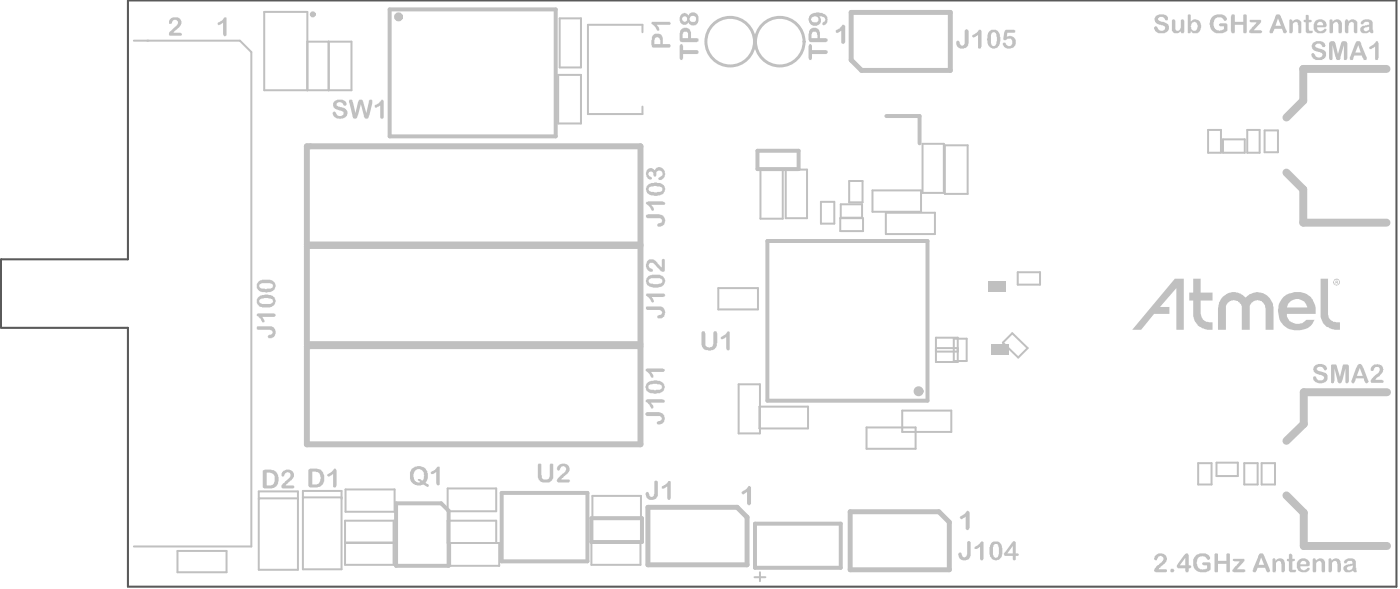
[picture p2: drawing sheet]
<svg xmlns="http://www.w3.org/2000/svg" width="238mm" height="100mm" viewBox="0 0 238 100" stroke-linecap="round" stroke-linejoin="round" font-family="sans-serif">
<circle cx="25.1" cy="6.9" r=".17" fill="#c0c0c0"/>
<g fill="none" stroke="#c0c0c0" stroke-width=".34">
<path d="M22.8 6.9h18.1l1.9 2v84.1h-20M52.4 7.1h7.5v8.3h-14.9v-13.4h7.4v13.4M56 7.1v8.3M95.1 12.7h3.9v8.3h-3.9zM95.3 3.1h3.7v8.4h-3.7zM109.4 5.5v-1.3h-9.3v15.2h9.3v-1.3M129.5 28.8h3.8v8.4h-3.8zM133.8 28.8h3.7v8.3h-3.7zM139.8 34.3h2.3v3.7h-2.3zM143.1 37.1h3.9v2.2h-3.9zM143.2 34.8h3.6v2.2h-3.6zM144.7 30.8h2.2v3.6h-2.2z"/>
<path d="M148.6 32.4h8.3v3.6h-8.3zM150.9 36.2h8.4v3.6h-8.4zM157.1 24.5h3.7v8.3h-3.7zM160.9 24.7h3.9v8.3h-3.9zM205.8 22.1h2.2v3.9h-2.2zM208.3 23.7h3.7v2.3h-3.7zM212.5 22.1h2.1v3.9h-2.1zM215.4 22.2h2.3v3.7h-2.3zM122.4 49h6.7v3.6h-6.7zM159.4 57.4h3.7v4.2h-3.7zM159.4 59.2h3.7M159.4 59.8h3.7"/>
<path d="M162.5 57.6h2.2v3.8h-2.2zM170.8 58.3l1.6-1.6 2.6 2.5-1.6 1.6zM173.4 46.3h3.8v2.1h-3.8zM125.8 65.4h3.7v8.3h-3.7zM129.4 69.2h8.2v3.7h-8.2zM147.6 72.7h8.4v3.6h-8.4zM153.7 69.8h8.3v3.7h-8.3zM204.1 78.8h2.3v3.6h-2.3zM207.2 78.7h3.7v2.3h-3.7zM212 78.8h2.2v3.6h-2.2zM214.9 78.8h2.3v3.6h-2.3zM30.2 93.7h8.4v3.6h-8.4z"/>
<path d="M44.1 83.6h6.6v13.3h-6.6zM50.7 84.8l-6.6 .1M51.6 83.5h6.6v13.3h-6.6zM58.2 84.6l-6.6 .1M58.8 88.6h8.2v7.5h-8.2zM58.8 92.3h8.2M58.8 92.4h8.2M58.9 83.3h8.3v3.8h-8.3zM76.3 83.1h8.2v3.9h-8.2zM76.7 92.4v3.8h8.3v-3.8h-8.7v-3.8h8.2v3.8M100.7 92.4h8.4v3.7h-8.4zM100.9 84.4h8.3v3.7h-8.3z"/>
<path d="M128.5 98.2h1.9M129.5 97.3v1.6"/>
</g>
<path d="M52.3 24.9h56.8v16.7h-56.8zM52.3 58.9h56.8v16.7h-56.8zM52.3 41.8h56.8v16.7h-56.8z" fill="none" stroke="#c0c0c0" stroke-width="1"/>
<path d="M66.4 1.6h28.3v21.6h-28.3zM151 19.7h5.6v4.7M129 25.6h7v3.2h-7zM130.7 41h27.3v27.2h-27.3zM67.5 85.6h7.7l1.2 1.3v9.3h-8.9zM85.5 83.8h14.6v11.7h-14.6zM100.7 88.1h8.7v4.1h-8.7zM128.6 89.1h14.6v7.5h-14.6z" fill="none" stroke="#c0c0c0" stroke-width=".68"/>
<path d="M145 2.1h16.9v9.9h-15.1l-1.8-1.8zM110.4 86.3h15.2l1.7 1.7v8.1h-16.9zM144.8 87.1h15.1l1.8 1.7v8.1h-16.9z" fill="none" stroke="#c0c0c0" stroke-width=".84"/>
<path d="M236.2 11.7h-14.2v5.4l-2.9 2.9M219.1 29.4l2.9 2.8v5.7h14.2M236.3 66.7h-14.2v5.4l-3 2.9M219.1 84.3l3 2.9v5.7h14.2" fill="none" stroke="#c0c0c0" stroke-width="1.4"/>
<g fill="#c0c0c0">
<path d="M168.4 47.8h2.9v1.9h-2.9z" fill-rule="evenodd"/>
<path d="M168.8 58.6h3v1.8h-3z" fill-rule="evenodd"/>
</g>
<g fill="#c0c0c0">
<path d="M119.5 56.5l.1-.1a.28 .28 0 0 1 .3-.1 .28 .28 0 0 1 .2 .4l.1 1.6a.64 .64 0 0 0 .2 .7 .64 .64 0 0 0 .7 0h.1a.71 .71 0 0 0 .3-.7v-1.6a.34 .34 0 0 1 .4-.4 .34 .34 0 0 1 .3 .4v1.7a1.32 1.32 0 0 1-1.9 1.2 1.24 1.24 0 0 1-.8-1.3z"/>
<path d="M122.8 57.4l.2-.2a1.4 1.4 0 0 0 1-.9l.3 .1v2.9a.3 .3 0 0 1-.3 .3 .3 .3 0 0 1-.3-.3v-2l-.2 .1a.55 .55 0 0 1-.7 .2z"/>
<path d="M126.3 83.7l.3-.2a1.14 1.14 0 0 0 .8-.8 .34 .34 0 0 1 .4 .1 .34 .34 0 0 1 .1 .3v2.3a.36 .36 0 0 1-.2 .6 .36 .36 0 0 1-.4-.5v-1.8l-.2 .1a.43 .43 0 0 1-.7 .2z"/>
<path d="M91.7 78.9h.1a.28 .28 0 0 1 .3 0 .28 .28 0 0 1 .1 .3l.1 1.7a.59 .59 0 0 0 .2 .6 .59 .59 0 0 0 .6 .1h.1a.63 .63 0 0 0 .4-.8v-1.6a.3 .3 0 0 1 .3-.3 .3 .3 0 0 1 .3 .3v1.5a1.19 1.19 0 0 1-1.6 1.4 1.07 1.07 0 0 1-1-1.4z"/>
<path d="M95 79.3a1.15 1.15 0 0 1 1.1-.4 1.15 1.15 0 0 1 .9 .8 1.7 1.7 0 0 1-.7 1.2l-.7 .7h1.3a.22 .22 0 0 1 .2 .2 .22 .22 0 0 1-.2 .2l-1.7 .1a.34 .34 0 0 1-.3-.5l.8-.9a1.21 1.21 0 0 0 .7-1.1 .52 .52 0 0 0-.5-.3 .52 .52 0 0 0-.5 .5 .29 .29 0 0 1-.4 .2 .29 .29 0 0 1-.1-.5z"/>
<path d="M142.4 5.1l.6-.2 .3-.4a.34 .34 0 0 1 .4-.3 .34 .34 0 0 1 .3 .4v2.6a.37 .37 0 0 1-.3 .2 .37 .37 0 0 1-.4-.1v-2.1l-.6 .4a.28 .28 0 0 1-.3-.1 .28 .28 0 0 1 0-.4z"/>
<path d="M111.5 81.9a.33 .33 0 0 1 .4-.1 .33 .33 0 0 1 .2 .4v1.6a.99 .99 0 0 1-1.3 1.2 1.11 1.11 0 0 1-.8-1.2 .42 .42 0 0 1 .6 .4 .38 .38 0 0 0 .4 .3 .38 .38 0 0 0 .4-.4z"/>
<path d="M112.7 82.7h.1a1.4 1.4 0 0 0 1-.8 .25 .25 0 0 1 .4-.1 .25 .25 0 0 1 .1 .4v2.4a.31 .31 0 0 1-.2 .4 .31 .31 0 0 1-.4-.1v-2.2l-.7 .4a.22 .22 0 0 1-.3-.1 .22 .22 0 0 1 0-.3z"/>
<path d="M223.8 62.4a1.44 1.44 0 0 1 2.2 0 .3 .3 0 0 1-.1 .5 .3 .3 0 0 1-.4-.2 .65 .65 0 0 0-.7-.4 .65 .65 0 0 0-.5 .5l.2 .3 .4 .1a1.23 1.23 0 0 1 1.2 .7 1.08 1.08 0 0 1-1.2 1.3 1.03 1.03 0 0 1-1.2-1.1h.1a.34 .34 0 0 1 .3 0 .34 .34 0 0 1 .2 .3 .83 .83 0 0 0 1.2 0v-.3l-.5-.3a1.32 1.32 0 0 1-1.3-1z"/>
<path d="M226.7 62.1l.3-.1a.57 .57 0 0 1 .7 .3l.5 1.8 .5-1.7a.55 .55 0 0 1 .8-.4l.3 .2v2.7a.3 .3 0 0 1-.3 .3 .3 .3 0 0 1-.3-.3v-2.2l-.6 2.1a.39 .39 0 0 1-.4 .4 .39 .39 0 0 1-.4-.5l-.5-2-.1 2.2a.26 .26 0 0 1-.2 .3 .26 .26 0 0 1-.3-.3z"/>
<path d="M233.6 62.4a1.43 1.43 0 0 1 1.8-.1 1.19 1.19 0 0 1-.3 1.6l-.5 .3-.4 .4h1.2a.25 .25 0 0 1 .3 .3 .25 .25 0 0 1-.3 .2h-1.6a.36 .36 0 0 1-.3-.3 .36 .36 0 0 1 .2-.4l.9-.8a.77 .77 0 0 0 .3-1.1 .57 .57 0 0 0-.6-.1 .57 .57 0 0 0-.3 .6h-.1a.3 .3 0 0 1-.4-.1 .3 .3 0 0 1 .1-.4z"/>
<path d="M223.6 7.3a1.75 1.75 0 0 1 1.9 0l.2 .2a.3 .3 0 0 1 .1 .4 .3 .3 0 0 1-.3 .1h-.2a.66 .66 0 0 0-.6-.6 .66 .66 0 0 0-.7 .4l.2 .3 .4 .2a1.19 1.19 0 0 1 1.3 .9v.1a1.05 1.05 0 0 1-1.3 .9 .95 .95 0 0 1-1.2-1.1 .47 .47 0 0 1 .5 .1 .47 .47 0 0 1 .2 .4 .7 .7 0 0 0 .7 .2 .7 .7 0 0 0 .5-.6l-.1-.2-.4-.1a1.32 1.32 0 0 1-1.4-1.1z"/>
<path d="M226.5 7.2l.3-.2a.6 .6 0 0 1 .7 .4l.4 1.8 .6-2a.69 .69 0 0 1 .9 0v2.8a.26 .26 0 0 1-.3 .2 .26 .26 0 0 1-.2-.3v-2.2l-.6 2a.39 .39 0 0 1-.3 .5 .39 .39 0 0 1-.4-.4l-.6-2.1v2.3a.3 .3 0 0 1-.4 .2 .3 .3 0 0 1-.2-.3z"/>
<path d="M233.2 8l.3-.2a1.14 1.14 0 0 0 .8-.7 .24 .24 0 0 1 .3-.1 .24 .24 0 0 1 .2 .3v2.7a.26 .26 0 0 1-.4 .2 .26 .26 0 0 1-.2-.3v-2l-.5 .4a.25 .25 0 0 1-.4 .1 .25 .25 0 0 1-.1-.4z"/>
<path d="M55.7 80.7l.3-.1a1.14 1.14 0 0 0 .8-.8 .28 .28 0 0 1 .3-.1 .28 .28 0 0 1 .2 .3v2.7a.26 .26 0 0 1-.3 .2 .26 .26 0 0 1-.3-.3v-2l-.3 .3a.42 .42 0 0 1-.7 0z"/>
<path d="M56.8 17.4a1.53 1.53 0 0 1 2.1 0 .34 .34 0 0 1 0 .6 .34 .34 0 0 1-.5-.4 .63 .63 0 0 0-1.1 .2v.2l.6 .2a1.16 1.16 0 0 1 1.3 1.2 1.35 1.35 0 0 1-1.3 .8 1.35 1.35 0 0 1-1.2-.9v-.2a.31 .31 0 0 1 .3-.1 .31 .31 0 0 1 .3 .3 .69 .69 0 0 0 .6 .4 .69 .69 0 0 0 .6-.4 .6 .6 0 0 0-.7-.5v-.1a1.03 1.03 0 0 1-1.1-1.2z"/>
<path d="M59.5 17h.1a.43 .43 0 0 1 .5 .4l.4 1.8 .5-1.8a.47 .47 0 0 1 .5-.4 .47 .47 0 0 1 .4 .5l.5 1.7 .4-1.8a.33 .33 0 0 1 .4-.4 .33 .33 0 0 1 .2 .5l-.6 2.2a.39 .39 0 0 1-.1 .5 .39 .39 0 0 1-.5 0l-.2-.4-.5-2.1-.6 2a.46 .46 0 0 1-.4 .5l-.4-.1-.1-.3-.6-2.3z"/>
<path d="M63.8 17.9l.4-.1 .6-.5a.34 .34 0 0 1 .5-.3l.1 2.7a.33 .33 0 0 1-.3 .5 .33 .33 0 0 1-.3-.4v-1.9l-.3 .2h-.2a.29 .29 0 0 1-.4 .2 .29 .29 0 0 1-.1-.4z"/>
<path d="M109.9 70.3l.3-.2h1.8a1.12 1.12 0 0 1 1.1 .7 1.12 1.12 0 0 1-.4 1.3l-.2 .1a.33 .33 0 0 1-.5 0 .33 .33 0 0 1 .1-.5l.1-.1a.43 .43 0 0 0 .5-.4 .43 .43 0 0 0-.5-.4h-1.8a.43 .43 0 0 1-.5-.5z"/>
<path d="M110 68l2.8-.1a.38 .38 0 0 1 .4 .2 .38 .38 0 0 1 0 .4h-2.3l.1 .2a.5 .5 0 0 1 .1 .8h-.1l-.4-.7-.4-.4h-.2z"/>
<path d="M110 62.8h3a.26 .26 0 0 1 .2 .3 .26 .26 0 0 1-.3 .2h-2l.1 .1a.5 .5 0 0 1 .1 .9l-.3-.3-.1-.3-.4-.4a.34 .34 0 0 1-.3-.5z"/>
<path d="M110 52.2l2.1-.1a1.05 1.05 0 0 1 1 .5 1.05 1.05 0 0 1 .1 1.1 .84 .84 0 0 1-1.2 .4 .44 .44 0 0 1 .5-.5l.1-.1a.48 .48 0 0 0 .1-.6 .48 .48 0 0 0-.6-.2h-1.7a.35 .35 0 0 1-.4-.5z"/>
<path d="M110.1 49.9h2.9a.26 .26 0 0 1 .3 .2 .26 .26 0 0 1-.1 .3l-.2 .1h-2l.1 .2a.55 .55 0 0 1 .2 .8l-.3-.1a1.73 1.73 0 0 0-.9-1.1z"/>
<path d="M110.2 44.5a1.11 1.11 0 0 1 1.9 .4l.6 .6v-1.1a.26 .26 0 0 1 .2-.4 .26 .26 0 0 1 .3 .3v1.6a.33 .33 0 0 1-.2 .3 .33 .33 0 0 1-.4-.1l-.8-.8a1.21 1.21 0 0 0-1.1-.6v.1a.53 .53 0 0 0-.1 .6 .53 .53 0 0 0 .4 .3 .3 .3 0 0 1 .1 .5 .3 .3 0 0 1-.5-.1 1.23 1.23 0 0 1-.4-1.6z"/>
<path d="M111 3.7h3.1a.27 .27 0 0 1 .2 .4 .27 .27 0 0 1-.4 .1h-2l.2 .3a.55 .55 0 0 1 .1 .7l-.3-.1a1.73 1.73 0 0 0-.9-1z"/>
<path d="M163.6 87.8l.3-.1 .6-.5a.34 .34 0 0 1 .4-.3 .34 .34 0 0 1 .3 .4l-.1 2.6a.31 .31 0 0 1-.4 .3 .31 .31 0 0 1-.2-.4v-1.9l-.4 .2a.31 .31 0 0 1-.5 .2 .31 .31 0 0 1 0-.5z"/>
<path d="M164.7 92.2l.1-.1a.34 .34 0 0 1 .4 0 .34 .34 0 0 1 .1 .3v1.7a1.06 1.06 0 0 1-1 1.2 1.06 1.06 0 0 1-1.1-1.1 .31 .31 0 0 1 .4-.2 .31 .31 0 0 1 .2 .4 .47 .47 0 0 0 .5 .4 .47 .47 0 0 0 .4-.5z"/>
<path d="M166 93a1.7 1.7 0 0 0 1-.8h.1a.25 .25 0 0 1 .3-.1 .25 .25 0 0 1 .1 .3v2.5a.31 .31 0 0 1-.2 .4 .31 .31 0 0 1-.4-.3v-2a.6 .6 0 0 1-.9 .3z"/>
<path d="M164.4 5.1a.28 .28 0 0 1 .3-.1 .28 .28 0 0 1 .2 .2l.1 1.9a1.14 1.14 0 0 1-.6 1 1.14 1.14 0 0 1-1.2 0v-.1a.73 .73 0 0 1-.1-1.1 .6 .6 0 0 1 .5 .7 .44 .44 0 0 0 .5 .1 .44 .44 0 0 0 .2-.5z"/>
<path d="M165.6 6.1l1-.8a.3 .3 0 0 1 .3-.2 .3 .3 0 0 1 .3 .3l-.1 2.6a.26 .26 0 0 1-.3 .3 .26 .26 0 0 1-.2-.4l-.1-1.9a.82 .82 0 0 1-.8 .3z"/>
<path d="M171.2 5.2l.1-.1h1.5a.27 .27 0 0 1 .1 .3 .27 .27 0 0 1-.3 .2h-1v.6a1.05 1.05 0 0 1 1.3 .4 1.05 1.05 0 0 1-.1 1.3 1.12 1.12 0 0 1-1.2 .4 1.12 1.12 0 0 1-.8-.9 .31 .31 0 0 1 .4-.1 .31 .31 0 0 1 .2 .3 .63 .63 0 0 0 .9 0 .63 .63 0 0 0 0-.9l-.7-.1-.1 .1h-.2a.25 .25 0 0 1-.3 .1 .25 .25 0 0 1-.1-.3z"/>
<path d="M28.9 3.4a1.32 1.32 0 0 1 1.8-.1 1.28 1.28 0 0 1-.6 1.7l-.6 .6h1.2a.26 .26 0 0 1 .3 .2 .26 .26 0 0 1-.3 .3l-1.9-.1-.1-.2 .2-.4 .8-.8a1.21 1.21 0 0 0 .6-1 .55 .55 0 0 0-.6-.2 .55 .55 0 0 0-.4 .5l-.1 .2a.34 .34 0 0 1-.4-.2 .34 .34 0 0 1 .1-.4z"/>
<path d="M37.1 3.9l.1-.1a1.57 1.57 0 0 0 1.1-.8h.3v2.7a.31 .31 0 0 1-.3 .5 .31 .31 0 0 1-.3-.4v-1.9l-.7 .4-.2-.2z"/>
<path d="M110 36.6l.4-.2h1.7a1.12 1.12 0 0 1 1 .5 1.12 1.12 0 0 1 .1 1.2 1.11 1.11 0 0 1-1.2 .4 .44 .44 0 0 1 .5-.5 .45 .45 0 0 0 .2-.6 .45 .45 0 0 0-.6-.3h-1.8a.34 .34 0 0 1-.3-.5z"/>
<path d="M110.1 34.3h3.1a.27 .27 0 0 1 .1 .4 .27 .27 0 0 1-.3 .1h-2l.3 .6a.22 .22 0 0 1 0 .4 .22 .22 0 0 1-.3-.1l-.1-.1a1.4 1.4 0 0 0-.9-.9z"/>
<path d="M110.1 29a.87 .87 0 0 1 1.4-.1 .89 .89 0 0 1 1.1-.5 .89 .89 0 0 1 .6 1 .87 .87 0 0 1-1 1.1 .34 .34 0 0 1 0-.3 .34 .34 0 0 1 .4-.2v-.1a.45 .45 0 0 0 .3-.4 .45 .45 0 0 0-.3-.4 .55 .55 0 0 0-.7 .1 .55 .55 0 0 0-.1 .7 .27 .27 0 0 1-.3 .1 .27 .27 0 0 1-.2-.3 .43 .43 0 0 0-.3-.5 .43 .43 0 0 0-.5 .3 .43 .43 0 0 0 .3 .5 .29 .29 0 0 1 .2 .5 .29 .29 0 0 1-.5 0 1.22 1.22 0 0 1-.4-1.4z"/>
<path d="M115.9 7.6a.28 .28 0 0 1 .3-.1 .28 .28 0 0 1 .2 .3v.7h2.2a.34 .34 0 0 1 .4 .4 .34 .34 0 0 1-.4 .3h-2.2l-.1 .8a.26 .26 0 0 1-.3 .2 .26 .26 0 0 1-.2-.3z"/>
<path d="M137.8 7.6a.29 .29 0 0 1 .4-.1 .29 .29 0 0 1 .1 .3v.7h2.3a.35 .35 0 0 1 .4 .4 .35 .35 0 0 1-.4 .3h-2.3v.8a.3 .3 0 0 1-.3 .2 .3 .3 0 0 1-.3-.2z"/>
<path d="M48 80.3h.1a1.06 1.06 0 0 1 1.2-.4 1.06 1.06 0 0 1 .8 1 1.57 1.57 0 0 1-.9 1.1l-.6 .6h1.3a.26 .26 0 0 1 .3 .3 .26 .26 0 0 1-.4 .2h-1.5a.34 .34 0 0 1-.3-.2 .34 .34 0 0 1 0-.3l.6-.8a1.27 1.27 0 0 0 .9-1 .43 .43 0 0 0-.4-.5l-.4 .1-.2 .2a.32 .32 0 0 1-.4 .5 .31 .31 0 0 1-.1-.5z"/>
<path d="M73.4 80.3l.1-.1a1.57 1.57 0 0 0 1.1-.8l.3 .1v2.7a.31 .31 0 0 1-.2 .4 .31 .31 0 0 1-.4-.4v-2l-.2 .2a.4 .4 0 0 1-.3 .3 .4 .4 0 0 1-.4-.3z"/>
<path d="M196.7 94.6a1.21 1.21 0 0 1 2.1 .3 1.38 1.38 0 0 1-1 1.3l-.5 .6h1.2a.25 .25 0 0 1 .3 .3 .25 .25 0 0 1-.3 .2h-1.6a.39 .39 0 0 1-.2-.5l.8-.9a1.08 1.08 0 0 0 .7-1 .59 .59 0 0 0-.7-.3 .59 .59 0 0 0-.4 .6l-.1 .1a.38 .38 0 0 1-.3-.2 .38 .38 0 0 1 0-.4z"/>
<path d="M203.7 94.5a2.16 2.16 0 0 1 2.2-.1l.1 .2a.36 .36 0 0 1 .1 .4 .36 .36 0 0 1-.4 .2l-.1-.1a.89 .89 0 0 0-.8-.5 .96 .96 0 0 0-.9 1.4 .93 .93 0 0 0 1.3 .8l.4-.1v-.5h-.4a.27 .27 0 0 1-.3-.2 .27 .27 0 0 1 .1-.3h1l.2 .1v1.1a2.2 2.2 0 0 1-2.7-.1 2.32 2.32 0 0 1 0-2.1z"/>
<path d="M206.9 94.2l.2-.1a.28 .28 0 0 1 .3 0 .28 .28 0 0 1 .1 .4v.9h1.4v-1a.3 .3 0 0 1 .3-.3 .3 .3 0 0 1 .3 .4v2.6a.3 .3 0 0 1-.3 .2 .3 .3 0 0 1-.3-.3v-1.1h-1.4v1.2a.3 .3 0 0 1-.4 .2 .3 .3 0 0 1-.2-.3z"/>
<path d="M210 95.1h1.7a.22 .22 0 0 1 .2 0 .22 .22 0 0 1 .1 .3l-1.3 1.4h1.2a.25 .25 0 0 1 .2 .3 .25 .25 0 0 1-.2 .2h-1.7a.32 .32 0 0 1-.3-.2 .32 .32 0 0 1 .2-.3l1.1-1.3h-.9l-.3-.1z"/>
<path d="M216.8 95.1a.27 .27 0 0 1 .4-.1 .27 .27 0 0 1 .1 .4 .87 .87 0 0 1 1-.4 .87 .87 0 0 1 .6 .9v1.2a.3 .3 0 0 1-.4 .2 .3 .3 0 0 1-.2-.3v-1a.48 .48 0 0 0-.4-.6 .48 .48 0 0 0-.5 .3v1.4a.3 .3 0 0 1-.4 .2 .3 .3 0 0 1-.2-.3z"/>
<path d="M219.6 94.3a.35 .35 0 0 1 .4-.1 .35 .35 0 0 1 .1 .4v.5h.2a.22 .22 0 0 1 .3 .2 .22 .22 0 0 1-.3 .2h-.2v1a.3 .3 0 0 0 0 .4 .3 .3 0 0 0 .5 0 .22 .22 0 0 1 .1 .3 .22 .22 0 0 1-.2 .1h-.2a.58 .58 0 0 1-.6-.1 .58 .58 0 0 1-.1-.6v-1.1a.25 .25 0 0 1-.4-.1 .25 .25 0 0 1 .1-.3h.3z"/>
<path d="M223.7 95a.43 .43 0 0 1 .5 .4 .82 .82 0 0 1 1-.4 .82 .82 0 0 1 .5 .9v1.1a.3 .3 0 0 1-.3 .3 .3 .3 0 0 1-.3-.3v-.9a.46 .46 0 0 0-.2-.7 .46 .46 0 0 0-.6 .3l-.1 1.3a.3 .3 0 0 1-.3 .3 .3 .3 0 0 1-.3-.3z"/>
<path d="M226.3 95.1h.1a.27 .27 0 0 1 .4-.1 .27 .27 0 0 1 0 .4 .8 .8 0 0 1 .9-.4 .8 .8 0 0 1 .6 .8v1.3a.26 .26 0 0 1-.3 .2 .26 .26 0 0 1-.2-.3v-1a.48 .48 0 0 0-.3-.6 .48 .48 0 0 0-.6 .3v1.3a.35 .35 0 0 1-.5 .3z"/>
<path d="M43.7 55.6l2.1-.1a1.03 1.03 0 0 1 1.1 .6 1.03 1.03 0 0 1-.4 1.3l-.3 .1a.34 .34 0 0 1-.5-.1 .34 .34 0 0 1 .2-.5 .45 .45 0 0 0 .5-.2v-.1a.43 .43 0 0 0-.4-.5h-1.9a.31 .31 0 0 1-.4-.1 .31 .31 0 0 1 0-.4z"/>
<path d="M43.7 53.5l.2-.2h2.6a.31 .31 0 0 1 .4 .3 .31 .31 0 0 1-.3 .3h-1.9l.2 .4a.25 .25 0 0 1 .2 .4 .25 .25 0 0 1-.4 0l-.3-.5-.7-.5z"/>
<path d="M196.8 2.8a1.75 1.75 0 0 1 2-.1l.1 .3a.33 .33 0 0 1-.1 .5 .33 .33 0 0 1-.4-.4 .58 .58 0 0 0-.7-.3 .58 .58 0 0 0-.4 .6l.4 .2a1.76 1.76 0 0 1 1.4 .9 1.14 1.14 0 0 1-1.5 1.2 .86 .86 0 0 1-.9-1.1 .43 .43 0 0 1 .6 .3 .62 .62 0 0 0 .7 .3 .62 .62 0 0 0 .4-.6l-.4-.3a1.32 1.32 0 0 1-1.3-1z"/>
<path d="M199.6 3.5a.31 .31 0 0 1 .4-.2 .31 .31 0 0 1 .2 .3v1a.46 .46 0 0 0 .3 .6 .46 .46 0 0 0 .6-.4v-1.2a.3 .3 0 0 1 .3-.3 .3 .3 0 0 1 .3 .3l-.1 2.1a.34 .34 0 0 1-.3-.1 .34 .34 0 0 1-.2-.3 .82 .82 0 0 1-.9 .4 .82 .82 0 0 1-.6-.9z"/>
<path d="M206.5 2.9a1.85 1.85 0 0 1 2.4 .1 .34 .34 0 0 1-.1 .5 .34 .34 0 0 1-.5-.3 .95 .95 0 0 0-1.1-.2 .95 .95 0 0 0-.5 1.1 1.09 1.09 0 0 0 .6 1 1.09 1.09 0 0 0 1.2-.1v-.5h-.5a.26 .26 0 0 1-.4-.2 .26 .26 0 0 1 .3-.3h1l.2 .1v1a2.02 2.02 0 0 1-2.4 .3 1.82 1.82 0 0 1-.2-2.4z"/>
<path d="M209.8 2.5v-.1a.34 .34 0 0 1 .4 .1 .34 .34 0 0 1 .1 .3v.9h1.5v-1a.3 .3 0 0 1 .3-.3 .3 .3 0 0 1 .3 .4v2.5a.3 .3 0 0 1-.3 .4 .3 .3 0 0 1-.3-.4v-1.1h-1.5v1.1a.34 .34 0 0 1-.3 .4 .34 .34 0 0 1-.3-.4z"/>
<path d="M212.9 3.4h1.7a.3 .3 0 0 1 .3 .2 .3 .3 0 0 1-.2 .4l-1.1 1.1h1.1a.25 .25 0 0 1 .3 .3 .25 .25 0 0 1-.3 .3h-1.7a.35 .35 0 0 1-.2-.4 .35 .35 0 0 1 .2-.3l1.1-1.2h-.9a.28 .28 0 0 1-.3-.1 .28 .28 0 0 1 0-.3z"/>
<path d="M219.6 3.4h.1a.3 .3 0 0 1 .3 0 .3 .3 0 0 1 .1 .3 .8 .8 0 0 1 1-.4 .8 .8 0 0 1 .6 .8v1.3a.26 .26 0 0 1-.3 .2 .26 .26 0 0 1-.2-.3l-.1-1.1a.43 .43 0 0 0-.3-.4 .43 .43 0 0 0-.5 .1l-.1 1.4a.3 .3 0 0 1-.3 .4 .3 .3 0 0 1-.3-.4z"/>
<path d="M222.4 2.6a.3 .3 0 0 1 .4-.1 .3 .3 0 0 1 .1 .5v.4h.3a.22 .22 0 0 1 .2 .2 .22 .22 0 0 1-.2 .2h-.3v1.2a.39 .39 0 0 0 .6 .2 .33 .33 0 0 1-.1 .5 .33 .33 0 0 1-.4 0 .54 .54 0 0 1-.5-.2 .54 .54 0 0 1-.1-.6v-1.1a.25 .25 0 0 1-.3-.1 .25 .25 0 0 1 .1-.3h.2z"/>
<path d="M226.5 3.4a.31 .31 0 0 1 .4-.1 .31 .31 0 0 1 .1 .4 .85 .85 0 0 1 1-.4 .85 .85 0 0 1 .6 .9v1.3l-.2 .2a.28 .28 0 0 1-.3-.1 .28 .28 0 0 1-.1-.3v-1a.46 .46 0 0 0-.3-.5 .46 .46 0 0 0-.5 .2l-.1 1.3a.3 .3 0 0 1-.3 .4 .3 .3 0 0 1-.3-.4z"/>
<path d="M229.2 3.4a.34 .34 0 0 1 .3 0 .34 .34 0 0 1 .2 .3 .81 .81 0 0 1 1-.4 .81 .81 0 0 1 .5 .9v1.2a.3 .3 0 0 1-.3 .3 .3 .3 0 0 1-.3-.4v-.9a.43 .43 0 0 0-.2-.6 .43 .43 0 0 0-.5 .2l-.2 .4v1a.3 .3 0 0 1-.4 .3 .3 .3 0 0 1-.2-.4z"/>
<path d="M231.2 62.2a.5 .5 0 0 1 .6-.3 .5 .5 0 0 1 .3 .6l.9 2a.37 .37 0 0 1-.1 .7 .37 .37 0 0 1-.5-.4l-.1-.4h-1.3l-.2 .6a.31 .31 0 0 1-.4 .2 .31 .31 0 0 1-.2-.4zM231.6 62.6l-.5 1.3h1z"/>
<path d="M231 7.2a.52 .52 0 0 1 .5-.2 .52 .52 0 0 1 .4 .5l.8 2.1a.34 .34 0 0 1 0 .6 .34 .34 0 0 1-.5-.3l-.2-.5h-1.3l-.2 .5a.33 .33 0 0 1-.4 .3 .33 .33 0 0 1-.1-.6zM231.4 7.7l-.5 1.2h.9z"/>
<path d="M52.6 79.8l1.3-.1a1.43 1.43 0 0 1 1.3 1.4v.2a1.49 1.49 0 0 1-.7 1.5l-1.6 .1a.43 .43 0 0 1-.4-.5zM53.2 80.2v2.2h.5a1.01 1.01 0 0 0 .9-1l-.1-.3a.87 .87 0 0 0-.9-.9z"/>
<path d="M110.1 65.3l.2-.2a2.15 2.15 0 0 1 2.9 .3v.1a1.06 1.06 0 0 1-1.1 1.4h-.8a1.1 1.1 0 0 1-1.3-1.4zM110.5 65.6a.53 .53 0 0 0 .1 .6 .53 .53 0 0 0 .5 .1h.9a.5 .5 0 0 0 .7-.3 .5 .5 0 0 0-.4-.6 2.21 2.21 0 0 0-1.8 .2z"/>
<path d="M110.1 47.3a2.19 2.19 0 0 1 2.1-.6 1.06 1.06 0 0 1 1.1 1 1.06 1.06 0 0 1-.9 1.1l-.4 .1a1.96 1.96 0 0 1-1.9-.7zM110.5 47.6v.1a.46 .46 0 0 0 .5 .5l.4 .1a1.65 1.65 0 0 0 1.4-.3v-.3a1.05 1.05 0 0 0-1.3-.4h-.6z"/>
<path d="M111.1 6.1a1 1 0 0 1 1.3-.3 1 1 0 0 1 .5 1.1v.6h.9a.32 .32 0 0 1 .5 .3 .32 .32 0 0 1-.5 .3l-2.8-.1v-1.2zM111.5 6.5v1h1v-.5a.56 .56 0 0 0-.3-.6 .56 .56 0 0 0-.6 0z"/>
<path d="M168.8 92.4a1.06 1.06 0 0 1 1.1-.3 1.06 1.06 0 0 1 .8 .8v.6a1.85 1.85 0 0 1-.2 1.4 1.03 1.03 0 0 1-1.1 .4 1.03 1.03 0 0 1-.8-.9l-.1-.5a2.07 2.07 0 0 1 .3-1.5zM169.2 92.8l-.1 .7a1.33 1.33 0 0 0 .3 1.3 .36 .36 0 0 0 .6-.2l.2-.5a1.95 1.95 0 0 0-.3-1.6h-.4z"/>
<path d="M172.3 92.3h.1a.31 .31 0 0 1 .4-.2 .31 .31 0 0 1 .2 .3l.1 1.7a.32 .32 0 0 1 .4 .4l-.5 .1v.4a.27 .27 0 0 1-.2 .3 .27 .27 0 0 1-.3-.3v-.4h-1.1a.35 .35 0 0 1-.4-.3 .35 .35 0 0 1 .2-.4zM172.5 92.9l-.9 1.2h.9z"/>
<path d="M168.4 5.5a1.09 1.09 0 0 1 1.2-.4 1.09 1.09 0 0 1 .7 1.1l.1 .4a1.81 1.81 0 0 1-.5 1.5 1.12 1.12 0 0 1-1.2 0 1.12 1.12 0 0 1-.5-1.2l-.1-.3zM168.9 5.7l-.1 .7a1.33 1.33 0 0 0 .3 1.4h.1a.62 .62 0 0 0 .5-.7v-.9a.45 .45 0 0 0-.2-.6l-.4-.1z"/>
<path d="M110.1 31.7a2.14 2.14 0 0 1 3.1 0 1.16 1.16 0 0 1-.9 1.5l-.6 .1a2.17 2.17 0 0 1-1.4-.4l-.3-.6zM110.5 31.9a.56 .56 0 0 0 .1 .6 .56 .56 0 0 0 .6 .1h.9a.49 .49 0 0 0 .7-.4 .49 .49 0 0 0-.6-.5 2.23 2.23 0 0 0-1.7 .2z"/>
<path d="M116 5a1.01 1.01 0 0 1 1.2-.2 1.01 1.01 0 0 1 .5 1.1v.6l1.3 .1a.38 .38 0 0 1 0 .4 .38 .38 0 0 1-.4 .2l-2.7-.1-.1-1.4zM116.4 5.6l-.1 .9h.9v-.4a.5 .5 0 0 0-.2-.6 .5 .5 0 0 0-.6 .1z"/>
<path d="M116 2.4a.77 .77 0 0 1 1.3 .2 .91 .91 0 0 1 1.2-.4 .91 .91 0 0 1 .5 1.1 .89 .89 0 0 1-.6 1 .89 .89 0 0 1-1.1-.5 .85 .85 0 0 1-1.2 .3 .85 .85 0 0 1-.2-1.2zM117.5 3.2a.55 .55 0 0 0 1.1 0 .55 .55 0 0 0-1.1 0zM116.2 3a.48 .48 0 0 0 .2 .7 .48 .48 0 0 0 .6-.2 .48 .48 0 0 0 0-.6h-.1a.42 .42 0 0 0-.7 .1z"/>
<path d="M138 5a1.01 1.01 0 0 1 1.2-.2 1.01 1.01 0 0 1 .5 1.1v.6l1.2 .1a.31 .31 0 0 1 .1 .3 .31 .31 0 0 1-.3 .3l-2.8-.1-.2-.3v-1.1zM138.3 5.6l-.1 .9h1v-.4a.62 .62 0 0 0-.7-.7z"/>
<path d="M138 2.5a2.15 2.15 0 0 1 2.9 .3 1.1 1.1 0 0 1-.5 1.5 .3 .3 0 0 1-.3-.3 .3 .3 0 0 1 .3-.3 .57 .57 0 0 0 .1-.6 .57 .57 0 0 0-.6-.3h-.4a.91 .91 0 0 1 .3 1.1 .91 .91 0 0 1-1.1 .5 1.06 1.06 0 0 1-.9-.7 1.06 1.06 0 0 1 .2-1.1zM138.2 3a.63 .63 0 0 0 .3 .8 .63 .63 0 0 0 .7-.1 .55 .55 0 0 0 .1-.6 .55 .55 0 0 0-.6-.3z"/>
<path d="M44.8 80l.3-.1h.9a1.44 1.44 0 0 1 1.5 1.6 1.41 1.41 0 0 1-1 1.5l-1.3 .1a.34 .34 0 0 1-.4-.4zM45.4 80.4v2.2h.5a.93 .93 0 0 0 .9-1.2 .88 .88 0 0 0-.9-1z"/>
<path d="M70.1 79.8a1.62 1.62 0 0 1 2.7 .5 1.91 1.91 0 0 1-.3 1.9h.1a.34 .34 0 0 1 .3 .2 .34 .34 0 0 1 .1 .3l-.2 .1-.4-.2a.42 .42 0 0 0-.7 0 1.63 1.63 0 0 1-1.9-2.1zM70.8 80a1.38 1.38 0 0 0 .3 2.1l.6-.1-.5-.3a.23 .23 0 0 1 .1-.2 .23 .23 0 0 1 .3 .1l.2 .1a.3 .3 0 0 0 .3-.1 .3 .3 0 0 0 .1-.3 1.41 1.41 0 0 0-.4-1.4l-.7-.1z"/>
<path d="M201.7 94.4h.1a.34 .34 0 0 1 .4-.3 .34 .34 0 0 1 .3 .4v1.7a.28 .28 0 0 1 .3 0 .28 .28 0 0 1 0 .4l-.3 .1-.1 .6h-.4l-.1-.6-1.3-.1a.41 .41 0 0 1 0-.7zM201.9 94.9l-.9 1.3h.9z"/>
<path d="M214.5 94.2l.2-.1a.6 .6 0 0 1 .7 .6l.9 2.1a.32 .32 0 0 1-.2 .5 .32 .32 0 0 1-.4-.3l-.2-.4h-1.3l-.1 .4a.33 .33 0 0 1-.5 .3 .33 .33 0 0 1-.1-.5zM214.8 94.8l-.4 1.3h.9z"/>
<path d="M221.1 95.4a1.13 1.13 0 0 1 1.3-.4 1.13 1.13 0 0 1 .7 1.2l-.3 .1h-1.3a.64 .64 0 0 0 .5 .6 .64 .64 0 0 0 .7-.2 .22 .22 0 0 1 .3 0 .22 .22 0 0 1-.1 .3 1.33 1.33 0 0 1-1.8-.1 1.79 1.79 0 0 1 0-1.5zM221.6 95.6l-.1 .4h1.1a.61 .61 0 0 0-.4-.5 .61 .61 0 0 0-.6 .1z"/>
<path d="M229.1 95.2a1.54 1.54 0 0 1 1.7 0l.2 .2v1.6a.25 .25 0 0 1 0 .4 .25 .25 0 0 1-.4-.1l-.2-.3a1.02 1.02 0 0 1-1.5 0 .77 .77 0 0 1 .9-1l.2-.1a.22 .22 0 0 0 .3 0 .22 .22 0 0 0 .1-.2 .43 .43 0 0 0-.7-.3l-.2 .2a.3 .3 0 0 1-.3 .2 .3 .3 0 0 1-.3-.3zM229.4 96.6a.44 .44 0 0 0 .4 .4 .44 .44 0 0 0 .5-.2 .4 .4 0 0 0 .1-.6l-.7 .1z"/>
<path d="M219.5 51.6l-.3 .7h3.5a1.77 1.77 0 0 0-1.4-1.4 1.77 1.77 0 0 0-1.8 .7zM218.5 50.6a3.5 3.5 0 0 1 5.1 .3l.1 .3a3.2 3.2 0 0 1 .4 2.2h-4.9a1.76 1.76 0 0 0 2.4 1.6h.2l.7-.6h1.4a3.3 3.3 0 0 1-4.2 1.6 3.2 3.2 0 0 1-2-3.3l.1-.3a2.32 2.32 0 0 1 .7-1.8zM227.2 48a.45 .45 0 0 1 .9 0 .45 .45 0 0 1-.9 0zM227.1 48a.6 .6 0 0 0 1.2 0 .6 .6 0 0 0-1.2 0zM227.6 47.8l.2 .1zM227.5 47.7v.5l.1-.1 .4 .1-.2-.2 .1-.2zM225 47.4h1.2v6a1.44 1.44 0 0 0 1.5 1.4h.5v1.3h-.9a2.51 2.51 0 0 1-1.6-.8l-.3-.4a2.21 2.21 0 0 1-.4-1.5zM208.2 50.6l-.1 .2a2.33 2.33 0 0 0-.6 1.7v3.6h1.3v-3.6a1.35 1.35 0 0 1 1.4-1.4 1.35 1.35 0 0 1 1.3 1.4v3.6h1.4v-3.6a1.31 1.31 0 0 1 .8-1.3 1.31 1.31 0 0 1 1.5 .4l.3 .4 .1 .5v3.6h1.3v-3.6a2.76 2.76 0 0 0-1.7-2.6 2.76 2.76 0 0 0-3.1 .7 2.63 2.63 0 0 0-2.6-.8l-.6 .2zM200.1 47.4h1.5v8.7h-1.2v-7.1l-2.8 3.2h1.6v1.2h-2.6l-2.2 2.7h-1.5zM203.3 47.4h1.2v2.4h2v1.3h-2v2.3a1.61 1.61 0 0 0 1.5 1.4h.5v1.3h-.6a2.9 2.9 0 0 1-2.5-1.7l-.1-.6v-2.7h-.7v-1.3h.7z"/>
<path d="M43.9 50.6a2.46 2.46 0 0 1 2.3-.3h.1a1 1 0 0 1 .6 1 1 1 0 0 1-.8 .9l-.8 .1a1.33 1.33 0 0 1-1.6-.8v-.6zM44.2 51a.63 .63 0 0 0 .8 .7 1.85 1.85 0 0 0 1.4-.2l.1-.3-.1-.3a2.73 2.73 0 0 0-2.2 0z"/>
<path d="M44 47.9l.1-.1a3.1 3.1 0 0 1 2.4 0 1.08 1.08 0 0 1 .3 1.3 1.08 1.08 0 0 1-1.2 .6h-.4a1.16 1.16 0 0 1-1.5-1.1v-.3zM44.2 48.4v.1a.66 .66 0 0 0 .9 .6h.5a.55 .55 0 0 0 .7-.1 .55 .55 0 0 0 .1-.7l-.7-.1a2.2 2.2 0 0 0-1.5 .2z"/>
<path d="M202.3 2.5h.1a.25 .25 0 0 1 .3-.1 .25 .25 0 0 1 .1 .4v.8a1.04 1.04 0 0 1 1.2-.2 1.04 1.04 0 0 1 .6 1.1v.1a1.03 1.03 0 0 1-1.2 1.1h-.2l-.3-.4-.1 .1a.26 .26 0 0 1-.3 .2 .26 .26 0 0 1-.2-.3zM203 4a1.07 1.07 0 0 0 .3 1.2 .57 .57 0 0 0 .7-.6v-.3a.58 .58 0 0 0-.4-.5 .58 .58 0 0 0-.6 .2z"/>
<path d="M217.4 2.5a.5 .5 0 0 1 .5-.1 .5 .5 0 0 1 .3 .6l.8 2.1a.32 .32 0 0 1 0 .5 .32 .32 0 0 1-.5-.3l-.1-.4h-1.3l-.2 .4a.36 .36 0 0 1-.5 .4 .36 .36 0 0 1-.1-.6zM217.7 3.1l-.4 1.3h.9z"/>
<path d="M223.9 3.7a1.12 1.12 0 0 1 1.3-.4 1.12 1.12 0 0 1 .8 1.1l-.2 .2h-1.4a.42 .42 0 0 0 .3 .6l.4 .1 .4-.2a.22 .22 0 0 1 .3-.2 .22 .22 0 0 1 .2 .2 1.3 1.3 0 0 1-1.6 .5 1.21 1.21 0 0 1-.6-1.5zM224.4 3.9v.4h1a.52 .52 0 0 0-.3-.6 .52 .52 0 0 0-.7 .2z"/>
<path d="M231.9 3.6a1.41 1.41 0 0 1 1.9 .1v1.4l.2 .3a.34 .34 0 0 1-.4 .3 .34 .34 0 0 1-.3-.4 1.11 1.11 0 0 1-1.5 .1 .68 .68 0 0 1 0-.7 .68 .68 0 0 1 .7-.3l.4-.2a.3 .3 0 0 0 .3-.4 .3 .3 0 0 0-.5-.1l-.3 .2a.3 .3 0 0 1-.4 .2 .3 .3 0 0 1-.2-.3zM232.3 4.8a.47 .47 0 0 0 .5 .5 .47 .47 0 0 0 .4-.5v-.3z"/>
<circle cx="199.7" cy="97" r=".33"/>
</g>
<g fill="none" stroke="#c0c0c0" stroke-width=".51">
<circle cx="53.3" cy="2.4" r=".25"/>
<circle cx="124.4" cy="7.1" r="4.1"/>
<circle cx="132.8" cy="7.1" r="4.1"/>
</g>
<g fill="none" stroke="#c0c0c0" stroke-width=".84">
<circle cx="67.9" cy="2.9" r=".34"/>
<circle cx="156.5" cy="66.6" r=".42"/>
</g>
<path d="M21.8 .1h216.1v99.7h-216.1v-44h-21.6v-11.7h21.6z" fill="none" stroke="#000" stroke-width=".17"/>
<path d="M21.8 .1h216.1v99.7h-216.1v-44h-21.6v-11.7h21.6z" fill="none" stroke="#5a5a5a" stroke-width=".34"/>
</svg>
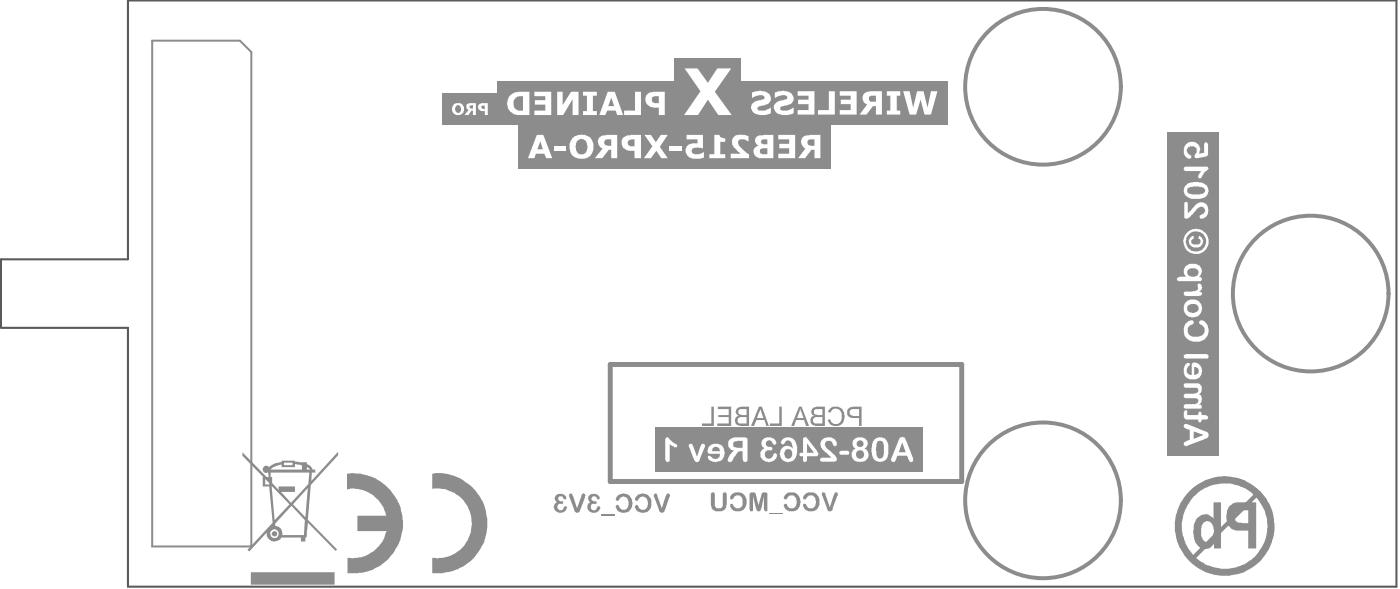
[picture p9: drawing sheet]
<svg xmlns="http://www.w3.org/2000/svg" width="238mm" height="100mm" viewBox="0 0 238 100" stroke-linecap="round" stroke-linejoin="round" font-family="sans-serif">
<path d="M25.9 6.9h15l1.9 2v84.1h-16.9z" fill="none" stroke="#8c8c8c" stroke-width=".34"/>
<path d="M103.9 62h59.9v19.9h-59.9z" fill="none" stroke="#8c8c8c" stroke-width=".84"/>
<path d="M75.3 15.9h9.4v5.4h-9.4z" fill-rule="evenodd" fill="#8c8c8c"/>
<g fill="#fff">
<path d="M81.5 17.9a.71 .71 0 0 0 .1 .7 .71 .71 0 0 0 .6 .3h.4v.7h.5v-2.1h-1.1zM82 18.1l.6-.1v.6l-.4-.1a.26 .26 0 0 1-.2-.1 .26 .26 0 0 1 0-.3z"/>
<path d="M80 18.1l.6-.2v.6h-.5l-.1-.2zM79.5 17.8v.3a.53 .53 0 0 0 .3 .6l-.7 .9h.7l.5-.8h.3v.8h.5v-2.1h-1.2z"/>
<path d="M77.2 17.9a1.06 1.06 0 0 0 .2 1.6 1.06 1.06 0 0 0 1.6-.5 1.06 1.06 0 0 0-.7-1.5h-.7zM77.6 18.1a.49 .49 0 0 1 .6-.2 .49 .49 0 0 1 .3 .5 .58 .58 0 0 1-.1 .6 .58 .58 0 0 1-.6 .1l-.3-.4z"/>
</g>
<path d="M114.8 10h11.4v11.3h-11.4z" fill-rule="evenodd" fill="#8c8c8c"/>
<path d="M116.6 11.6h2.2l1.8 2.5 1.6-2.5h2.4l-2.8 4 2.8 4h-2.2l-1.8-2.6-1.7 2.6h-2.4l2.8-4.1z" fill="#fff"/>
<path d="M198.9 22.4h8.7v55.1h-8.7z" fill-rule="evenodd" fill="#8c8c8c"/>
<g fill="#fff">
<path d="M201.7 69.9a.33 .33 0 0 1 .5 0 .33 .33 0 0 1 0 .4 .3 .3 0 0 0 .2 .4 .3 .3 0 0 0 .3-.1h1.4l.1-.4a.27 .27 0 0 1 .3-.2 .27 .27 0 0 1 .2 .3v.3h.7a.4 .4 0 0 1 .4 .5 .4 .4 0 0 1-.6 .3h-.5l-.1 .2a.26 .26 0 0 1-.3 .3 .26 .26 0 0 1-.2-.4v-.1h-1.4a.78 .78 0 0 1-.9-.2 .78 .78 0 0 1-.2-.9z"/>
<path d="M201.6 65.4l.2-.2h1.8a.98 .98 0 0 1 1.1 .5 .98 .98 0 0 1-.3 1.2l-.1 .2a1.1 1.1 0 0 1 .3 1.3l-.3 .3 .1 .1a.34 .34 0 0 1 .3 .4 .34 .34 0 0 1-.4 .3h-2.2a.38 .38 0 0 1-.5-.4 .38 .38 0 0 1 .5-.4h1.3a.63 .63 0 0 0 .7-.8l-.3-.2h-1.7a.38 .38 0 0 1-.5-.3 .38 .38 0 0 1 .5-.4l1.5-.1a.47 .47 0 0 0 .5-.5 .47 .47 0 0 0-.5-.4h-1.5a.46 .46 0 0 1-.5-.6z"/>
<path d="M201.6 60.4l.4-.2h3.4a.38 .38 0 0 1 .5 .4 .38 .38 0 0 1-.5 .4h-3.4a.38 .38 0 0 1-.4-.2 .38 .38 0 0 1 0-.4z"/>
<path d="M201.9 55.1a1.91 1.91 0 0 1 1.3-.6v.1a.38 .38 0 0 1 .1 .5 .38 .38 0 0 1-.5 .2 1.14 1.14 0 0 0-.3 1.4 1.14 1.14 0 0 0 1.3 .6 1.18 1.18 0 0 0 1.3-1.6l-.4-.4a.4 .4 0 0 1-.4-.6 .4 .4 0 0 1 .6-.1 1.89 1.89 0 0 1 .9 2.1 1.89 1.89 0 0 1-1.9 1.4 1.99 1.99 0 0 1-2.2-1.2l-.1-1.1z"/>
<path d="M201.6 49.8l.2-.2 1.5-.1a.64 .64 0 0 0 .7-.2 .64 .64 0 0 0 0-.7v-.1a.36 .36 0 0 1 .5-.2 .36 .36 0 0 1 .2 .5v.5l-.4 .3a.36 .36 0 0 1 .4 .2 .36 .36 0 0 1-.2 .5h-2.6a.34 .34 0 0 1-.3-.5z"/>
<path d="M201.7 34.5a.32 .32 0 0 1 .5-.2 .32 .32 0 0 1 .1 .5v1.5l.6-.5a2.71 2.71 0 0 1 1.6-1.4 1.3 1.3 0 0 1 1.4 1.4 1.5 1.5 0 0 1-1.2 1.4 .38 .38 0 0 1-.3-.4 .38 .38 0 0 1 .4-.4 .67 .67 0 0 0 .3-1 .67 .67 0 0 0-1.1 0l-.7 .9a2.11 2.11 0 0 1-1.3 .9l-.3-.2z"/>
<path d="M201.6 28.5l.3-.2h3.5a.31 .31 0 0 1 .4 .3 .31 .31 0 0 1-.2 .3l-.6 .5-.3 .7a.31 .31 0 0 1-.5 .2 .31 .31 0 0 1 0-.5l.4-.7-2.7-.1a.3 .3 0 0 1-.3-.1 .3 .3 0 0 1 0-.4z"/>
<path d="M202.1 24.5a1.36 1.36 0 0 1 1.8-.2 1.36 1.36 0 0 1 .3 1.8l.9-.1v-1.4a.35 .35 0 0 1 .3-.4 .35 .35 0 0 1 .4 .4l-.1 1.9-.3 .2-1.5 .2a.4 .4 0 0 1-.4-.2 .4 .4 0 0 1 .1-.5 .82 .82 0 0 0-.1-1.3 .82 .82 0 0 0-1.3 .5 1.21 1.21 0 0 0 .7 1.1v.1a.35 .35 0 0 1-.1 .4 .35 .35 0 0 1-.5-.1 1.63 1.63 0 0 1-.2-2.4z"/>
<path d="M201.6 72.3a.6 .6 0 0 0 .5 .7l.6 .1v1.7l-.5 .3a.41 .41 0 0 0-.6 .4 .41 .41 0 0 0 .6 .3l3-1.1a.67 .67 0 0 0 .7-.7 .67 .67 0 0 0-.7-.7l-3-1.2h-.4zM203.3 73.4l1.7 .6-1.7 .7z"/>
<path d="M201.9 62a1.6 1.6 0 0 0 .9 2.5 1.52 1.52 0 0 0 2-1.5 1.28 1.28 0 0 0-1.7-1.3l-.1 2.1a.77 .77 0 0 1-.8-.4 .77 .77 0 0 1 0-.8l.2-.3a.31 .31 0 0 0 .3-.2 .31 .31 0 0 0-.2-.4h-.3zM203.4 62.4a.68 .68 0 0 1 .8 .7 .68 .68 0 0 1-.8 .7z"/>
<path d="M201.9 51.5a1.59 1.59 0 0 0 1.1 2.5 1.59 1.59 0 0 0 1.6-2.3 1.76 1.76 0 0 0-2.7-.2zM202.2 52.1a1.18 1.18 0 0 1 2 .2 1.03 1.03 0 0 1-1.6 .8l-.1-.1a.73 .73 0 0 1-.3-.9z"/>
<path d="M201.9 45.3a1.33 1.33 0 0 0 .2 1.8l-1.2 .1a.35 .35 0 0 0-.4 .3 .35 .35 0 0 0 .4 .3h3.4a.38 .38 0 0 0 .4-.4 .38 .38 0 0 0-.4-.3h-.1a1.17 1.17 0 0 0 .5-1.2 1.17 1.17 0 0 0-.9-.9 1.71 1.71 0 0 0-1.9 .3zM202.2 46.1a1.18 1.18 0 0 1 2 .1 .96 .96 0 0 1-.6 .9 .96 .96 0 0 1-1-.2 .76 .76 0 0 1-.4-.8z"/>
<path d="M202.7 40.5a1.13 1.13 0 0 0 .1 1.2 1.13 1.13 0 0 0 1.2 .4 1.05 1.05 0 0 0 .9-.9 1.05 1.05 0 0 0-.6-1.1l-.2 .5a.54 .54 0 0 1 .4 .7 .54 .54 0 0 1-.7 .3 .57 .57 0 0 1-.8-.3 .57 .57 0 0 1 .3-.7h.1l-.1-.5zM202 39.8a2.15 2.15 0 0 0 .7 3.2 2.15 2.15 0 0 0 3.1-1.3 2.15 2.15 0 0 0-1.9-2.7 2.12 2.12 0 0 0-1.9 .8zM202.2 40.2a1.72 1.72 0 0 1 2.9-.1 1.72 1.72 0 0 1-1.2 2.7h-.1a1.74 1.74 0 0 1-1.6-1l-.2-.9z"/>
<path d="M201.8 31.7a1.48 1.48 0 0 0 1.5 2.1h.2a2.1 2.1 0 0 0 2.3-.9 1.43 1.43 0 0 0-1.5-1.9 3.9 3.9 0 0 0-2.1 .3zM202.2 32.1a2.49 2.49 0 0 1 1.9-.4l.3 .1a.7 .7 0 0 1 .7 .2 .7 .7 0 0 1 .1 .7 2.76 2.76 0 0 1-1.8 .4h-.4a.75 .75 0 0 1-.8-1z"/>
</g>
<path d="M84.7 13.9h30.1v7.4h-30.1z" fill-rule="evenodd" fill="#8c8c8c"/>
<g fill="#fff">
<path d="M108.2 15.6h1v4h-2.9v-.8h1.9z"/>
<path d="M99.3 15.6h2.4v.7h-.7v2.6h.7v.7h-2.4v-.7h.7v-2.6h-.7z"/>
<path d="M94.9 15.6h.9v2.3l1.5-2.3h1.2v4h-1v-2.7l-1.6 2.7h-1z"/>
<path d="M91 15.6h2.9v4h-2.9v-.8h1.9v-1h-1.8v-.8h1.8v-.6h-1.9z"/>
<path d="M110 16.3a1.37 1.37 0 0 0 1 1.9l1.2 .1v1.3h1v-4h-1.7a1.59 1.59 0 0 0-1.5 .7zM111 16.6l.5-.2h.7v1.1h-.3a.7 .7 0 0 1-.7-.2 .7 .7 0 0 1-.2-.7z"/>
<path d="M103.5 15.6l-1.4 4h1l.3-.8h1.5l.2 .8h1l-1.4-4zM104.1 16.6l.5 1.5h-1z"/>
<path d="M86.8 16.3a2.07 2.07 0 0 0-.1 2.3 2.07 2.07 0 0 0 2 1h1.5v-4h-1.5a2.12 2.12 0 0 0-1.6 .5zM87.8 16.6l.6-.2h.7v2.4a1.26 1.26 0 0 1-1.5-.5 1.26 1.26 0 0 1 .2-1.6z"/>
</g>
<path d="M88.2 21.3h53.2v7.4h-53.2z" fill-rule="evenodd" fill="#8c8c8c"/>
<g fill="#fff">
<path d="M132.6 22.9h2.8v4h-2.8v-.8h1.8v-.9h-1.7v-.7h1.7v-.8h-1.8z"/>
<path d="M124.9 23.4h.1a1.36 1.36 0 0 1 1.5-.5l1 .2v.9a1.55 1.55 0 0 0-1.7-.1 1.18 1.18 0 0 0 .6 1.4l.6 .6 .6 .3v.7h-3.1v-.8h1.7l-.6-.5a2.12 2.12 0 0 1-.9-1.9z"/>
<path d="M121.7 22.9h.8a.88 .88 0 0 0 1 .6v.6h-.8v2.1h.8v.7h-2.7v-.7h.9z"/>
<path d="M117 22.9h2.7v2.3h-.2a1.49 1.49 0 0 0-1.5 .1l-.1 .1a.7 .7 0 0 0 .2 .7 .7 .7 0 0 0 .7 .1l.6-.1 .5-.2v.9l-.8 .2a1.97 1.97 0 0 1-2.1-.6 1.2 1.2 0 0 1 .5-1.9l.4-.1h.9v-.7h-1.8z"/>
<path d="M114.1 24.8h2.1v.8h-2.1z"/>
<path d="M109.8 22.9h1.1l.8 1.3 .9-1.3h1.1l-1.3 2.1 1.3 1.9h-1.1l-.8-1.3-.9 1.3h-1.2l1.4-2z"/>
<path d="M94.4 24.8h2v.8h-2z"/>
<path d="M137.6 24l.3-.3h.8v1.1h-.3a.68 .68 0 0 1-.8-.8zM136.6 23.5a1.21 1.21 0 0 0 .6 1.7l-1.2 1.7h1.1l1.1-1.4h.5v1.4h1.1v-4l-2.5 .1z"/>
<path d="M128.7 23.5a1.11 1.11 0 0 0 .5 1.3 1.03 1.03 0 0 0-.8 1 1.03 1.03 0 0 0 .8 1l2.5 .1v-4l-2.4 .1zM129.7 23.9l.2-.2h.8v.8h-.2a.56 .56 0 0 1-.6 0 .56 .56 0 0 1-.2-.6zM129.5 25.4l.3-.2h.9v1a1.18 1.18 0 0 1-1.2-.3z"/>
<path d="M106 23.6a1.44 1.44 0 0 0 1.5 2h.6v1.3h1.1v-4h-1.7a2.31 2.31 0 0 0-1.5 .7zM107 24l.6-.3h.5v1.2h-.3a.66 .66 0 0 1-.7-.2 .66 .66 0 0 1-.1-.7z"/>
<path d="M103 23.9l.3-.2h.8v1.1l-.7-.1a.5 .5 0 0 1-.5-.3 .5 .5 0 0 1 .1-.5zM102 23.5a1.2 1.2 0 0 0 .7 1.7l-1.4 1.7h1.3l1.1-1.4h.4v1.4h1v-4l-2.4 .1z"/>
<path d="M97.4 23.5a2.36 2.36 0 0 0 .5 3.2 2.25 2.25 0 0 0 3-.7 2.29 2.29 0 0 0-.7-2.8 2.54 2.54 0 0 0-2.8 .3zM98.2 24.1a.95 .95 0 0 1 1.1-.4 .95 .95 0 0 1 .7 .9 1.35 1.35 0 0 1-.4 1.5l-.1 .1a.97 .97 0 0 1-1.4-1l-.1-.4z"/>
<path d="M91.5 22.9l-1.6 4h1.1l.3-.8h1.4l.4 .8h1l-1.6-4zM92 24l.5 1.4h-1z"/>
</g>
<g fill="#8c8c8c">
<path d="M111.4 84.1h.1a.27 .27 0 0 1 .3-.2 .27 .27 0 0 1 .2 .4l.7 2.2 .7-2.1a.4 .4 0 0 1 .3-.4 .4 .4 0 0 1 .4 .1v.5l-.8 2a.57 .57 0 0 1-.4 .6 .57 .57 0 0 1-.6-.2l-.9-2.5z"/>
<path d="M108.6 84.2h.1a1.59 1.59 0 0 1 1.7 .1 1.59 1.59 0 0 1 .6 1.7v.1a1.43 1.43 0 0 1-2 1 .98 .98 0 0 1-.7-1.1 .34 .34 0 0 1 .3 0 .34 .34 0 0 1 .2 .3 .86 .86 0 0 0 1 .4 .86 .86 0 0 0 .6-.9 1.19 1.19 0 0 0-.5-1.2 .48 .48 0 0 0-.7-.1l-.4 .4a.3 .3 0 0 1-.5 .2 .3 .3 0 0 1 0-.5z"/>
<path d="M105 84.6a1.49 1.49 0 0 1 2.3-.2 1.81 1.81 0 0 1-.5 2.7 1.35 1.35 0 0 1-1.9-1 .3 .3 0 0 1 .3-.2 .3 .3 0 0 1 .3 .3 .84 .84 0 0 0 1 .5 .84 .84 0 0 0 .6-.9 1.05 1.05 0 0 0-.7-1.3 .88 .88 0 0 0-1 .6 .3 .3 0 0 1-.4 0 .3 .3 0 0 1 0-.4z"/>
<path d="M46.3 90.8a.45 .45 0 0 0 .9 0 .45 .45 0 0 0-.9 0zM41.3 76.9v.6l3.5 3.6v1.6h1.1l.5 6.2-4.3 4.6 .4 .3 2.9-3.2a1.32 1.32 0 0 0 .9 1.4 1.32 1.32 0 0 0 1.6-.6h3.4v.7h.7v-.7h.2l.1-.2 .1-2.3 4.8 4.8 .2-.2-5-5.1 .5-5.9 4.7-5.1v-.6l-4.6 5 .1-1.4h.6v-.5h-.4l-.6-.8-.4-.1v-.4l-.9 .1-1.2-.2v-.1h-2.2v.2h-.3a2.88 2.88 0 0 0-1.8 .8v.1a.62 .62 0 0 0-.9-.1 .62 .62 0 0 0-.1 .8 .62 .62 0 0 0 .8 .2l.1 .7h-.4zM48.4 78.7h1.4v.4h-1.4zM46.1 79.8l.4-.3 1.3-.5h.2v.5h2.2v-.5l1.2 .1v.8zM52.3 79.5l.3 .1 .2 .3h-.5zM52.4 83l-.4 5-2.1-2.2zM49.7 86l2.2 2.5-.1 2.5h-3.8a1.31 1.31 0 0 0-1.1-1.6v-.3zM46 90.8a.75 .75 0 0 1 1.5 0 .75 .75 0 0 1-1.5 0zM46.3 82.7l3 3.1-2.5 2.7zM46.1 80.4h6.6l-.2 1.9-2.9 3.2-1.7-1.8h2.3v-1h-2.7v.6l-1.1-1.1v-1.1h-.3zM45.2 81.5l.7 .7v.2h-.7zM42.7 97.3v2.2h14.3v-2.2z"/>
<path d="M59.1 80.6v2.7a5.5 5.5 0 0 1 5.9 2.6l.3 .3 .5 1.5h-4.9v2.6h5l-.2 .4a5.7 5.7 0 0 1-6.2 4.2h-.3v2.6h.2a10.4 10.4 0 0 0 4.2-.7 8.5 8.5 0 0 0 5-8.6 8.5 8.5 0 0 0-6.7-7.5 6.1 6.1 0 0 0-2.8-.1zM73.6 80.6v2.6a5.9 5.9 0 0 1 6.8 5.8 5.9 5.9 0 0 1-6.8 5.9v2.6h.2a8.4 8.4 0 0 0 8.3-4.6l.4-.9a8.5 8.5 0 0 0-1.9-9l-.1-.1a8.5 8.5 0 0 0-2.7-1.8h-.2a7.9 7.9 0 0 0-3.5-.6z"/>
</g>
<path d="M102.4 87.6h2.3" fill="none" stroke="#8c8c8c" stroke-width=".25"/>
<g fill="#8c8c8c">
<path d="M100.4 84.2h.1a1.06 1.06 0 0 1 1.7 .6 .26 .26 0 0 1-.3 .2 .26 .26 0 0 1-.2-.3 .45 .45 0 0 0-.7-.2 .45 .45 0 0 0 0 .7l.2 .1a.3 .3 0 0 1 .4 0 .3 .3 0 0 1 0 .4 .3 .3 0 0 1-.4 0 .55 .55 0 0 0-.6 .5 .55 .55 0 0 0 .4 .6 .55 .55 0 0 0 .7-.4 .3 .3 0 0 1 .4-.3 .3 .3 0 0 1 .1 .5 1.17 1.17 0 0 1-1.1 .6 1.17 1.17 0 0 1-1-.7 .94 .94 0 0 1 .5-1.1 .92 .92 0 0 1-.2-1.2z"/>
<path d="M96.9 84.1h.1a.29 .29 0 0 1 .4-.1 .29 .29 0 0 1 .1 .4l.8 2.1 .8-2.1a.34 .34 0 0 1 .1-.4 .34 .34 0 0 1 .4 0 .24 .24 0 0 1 .1 .2 .24 .24 0 0 1-.1 .2l-.8 2.3a.51 .51 0 0 1-.6 .5 .51 .51 0 0 1-.4-.6l-.9-2.1z"/>
<path d="M94.7 84.3a1.11 1.11 0 0 1 1.7 .3 .26 .26 0 0 1-.2 .3 .26 .26 0 0 1-.3-.3 .45 .45 0 0 0-.8 0 .45 .45 0 0 0 .5 .7 .24 .24 0 0 1 .3 .2 .24 .24 0 0 1-.3 .2h-.1a.56 .56 0 0 0-.5 .9 .56 .56 0 0 0 1-.1 .29 .29 0 0 1 .2-.4 .29 .29 0 0 1 .4 .2 .29 .29 0 0 1-.2 .3 1.05 1.05 0 0 1-1.7 .4 .84 .84 0 0 1-.4-.8 .84 .84 0 0 1 .5-.8 .81 .81 0 0 1-.1-1.1z"/>
<path d="M141.3 69.6a1.53 1.53 0 0 1 1.8-.2 1.53 1.53 0 0 1 .7 1.7 1.46 1.46 0 0 1-2 1.3l-.4-.3-.4-.5v-.2l.4-.1a.99 .99 0 0 0 1.2 .8 .99 .99 0 0 0 .8-1.2 1.09 1.09 0 0 0-.4-1.1 1.09 1.09 0 0 0-1.3 0l-.3 .4-.4-.1z"/>
<path d="M132.7 69.2h.5v3.3h-2.1v-.5h1.6z"/>
<path d="M122.3 69.2h2.3v3.3h-2.4v-.5h1.9v-1.1h-1.7v-.3h1.7v-1h-1.8z"/>
<path d="M121.2 69.2h.4v3.3h-2v-.5h1.6z"/>
<path d="M203.8 88.3a4.2 4.2 0 0 0 .3 4.6 1.69 1.69 0 0 0 2.7-.5v.9h1.2v-7.9h-1.3v2.8a1.72 1.72 0 0 0-1.7-.6h-.4zM204.9 89a1 1 0 0 1 1.7 .5 2.98 2.98 0 0 1-.1 2.2 1 1 0 0 1-1 .5 1 1 0 0 1-.8-.8l-.1-.9a2.27 2.27 0 0 1 .3-1.5zM209.2 86.3a3.4 3.4 0 0 0 .2 3.3l.4 .4a2.79 2.79 0 0 0 2 .3h.8v3h1.4v-7.9h-2.2a2.41 2.41 0 0 0-2.6 .9zM210.4 87.1a1.74 1.74 0 0 1 1.6-.3h.6v2.2l-1.2-.1a1.01 1.01 0 0 1-1.1-1.1zM202.6 83.5a8.5 8.5 0 0 0 1.2 13 8.5 8.5 0 0 0 12.6-3.6 8.5 8.5 0 0 0-6-11.7 8.8 8.8 0 0 0-7.8 2.3zM203.4 84.4a7.3 7.3 0 0 1 12 2.5 7.3 7.3 0 0 1-7.3 9.9 7.3 7.3 0 0 1-5.8-10.9zM202.7 94.9l.6 .5 11.3-11.3-.5-.5z"/>
<path d="M144.4 69.6a1 1 0 0 0 0 1.1 1 1 0 0 0 1.1 .4h.8v1.4h.5v-3.3l-1.6 .1a.45 .45 0 0 0-.6 .2zM144.8 69.8l.3-.2h1.2v1.2h-.8a.66 .66 0 0 1-.7-1z"/>
<path d="M138.3 69.6a.84 .84 0 0 0 .4 1.2 .82 .82 0 0 0-.7 .7 .82 .82 0 0 0 .5 .8l.3 .2h1.7v-3.3h-1.4l-.5 .1zM138.7 69.8l.2-.2h1.2v1h-.8a.62 .62 0 0 1-.6-.8zM138.5 71.3l.1-.1a.67 .67 0 0 1 .7-.3h.8v1.1h-1.3l-.3-.3z"/>
<path d="M136.1 69.2l-1.3 3.3h.5l.3-1.1h1.4l.3 1.1h.5l-1.3-3.3zM136.3 69.5l.6 1.6h-1.1z"/>
<path d="M129.3 69.2l-1.4 3.3h.5l.5-1.1h1.3l.3 1.1h.5l-1.2-3.3zM129.5 69.5l.5 1.6h-1.1z"/>
<path d="M125.5 69.5v.1a.77 .77 0 0 0 .3 1.1 .91 .91 0 0 0-.6 1.1 .91 .91 0 0 0 1 .7h1.4v-3.3h-1.4zM125.8 69.8l.3-.2h1.1v1h-.9l-.4-.2a.48 .48 0 0 1-.1-.6zM125.7 71.1l.4-.2h1.1v1.1h-.8a.61 .61 0 0 1-.6-.2 .61 .61 0 0 1-.1-.7z"/>
</g>
<path d="M111.7 72.7h45.5v7.5h-45.5z" fill-rule="evenodd" fill="#8c8c8c"/>
<g fill="#fff">
<path d="M143 76.8l1.3-.1a.34 .34 0 0 1 .4 .3 .34 .34 0 0 1-.4 .4h-1a.39 .39 0 0 1-.3-.6z"/>
<path d="M139.9 74.9a1.66 1.66 0 0 1 2.6 .2v.1a.39 .39 0 0 1 0 .5 .39 .39 0 0 1-.6 0 .93 .93 0 0 0-1-.7 .83 .83 0 0 0 .1 1.4l.6 .5a2.11 2.11 0 0 1 .9 1.3v.2l-.3 .1h-2.1a.36 .36 0 0 1-.4-.4 .36 .36 0 0 1 .5-.2h1.4l-.7-.8a1.63 1.63 0 0 1-1-2.1z"/>
<path d="M129.8 74.9a1.51 1.51 0 0 1 2.4 .3 .36 .36 0 0 1-.2 .5 .36 .36 0 0 1-.4-.5 .56 .56 0 0 0-1-.1 .56 .56 0 0 0 .4 .9 .36 .36 0 0 1 .4 0 .36 .36 0 0 1 .1 .5l-.1 .1a.76 .76 0 0 0-1.1 .5 .76 .76 0 0 0 .8 .9l.3-.1 .2-.3a.44 .44 0 0 1 .6-.5v.1a.8 .8 0 0 1-.5 1.2 1.41 1.41 0 0 1-2.2-1.2 .45 .45 0 0 1 .3-.6l.2-.3a.3 .3 0 0 0-.2-.4z"/>
<path d="M117.4 75.6l.1-.1a.43 .43 0 0 1 .6 .3l.6 1.9 .6-1.8a.4 .4 0 0 1 .5-.4 .4 .4 0 0 1 .3 .6l-.9 1.9a.51 .51 0 0 1-.5 .6 .51 .51 0 0 1-.5-.6l-.7-1.8a.4 .4 0 0 1-.1-.6z"/>
<path d="M113.4 74.5l.1-.1a.6 .6 0 0 1 .7 .4l.8 .7a.31 .31 0 0 1 .4 .4 .31 .31 0 0 1-.6 .1l-.7-.4v2.7a.38 .38 0 0 1-.4 .3 .38 .38 0 0 1-.4-.4z"/>
<path d="M153.2 74.6l-1.3 3.3a.4 .4 0 0 0 .1 .6 .4 .4 0 0 0 .6-.3l.2-.7h1.7l.3 .7a.41 .41 0 0 0 .6 .3 .41 .41 0 0 0 .1-.6l-1.1-2.8a.65 .65 0 0 0-.4-.7 .65 .65 0 0 0-.7 .2zM153.7 75.2l.6 1.7h-1.2z"/>
<path d="M149 74.7v.1a2.46 2.46 0 0 0-.5 1.7v.1a2.32 2.32 0 0 0 .7 1.8h.1a1.48 1.48 0 0 0 2-1.6 2.39 2.39 0 0 0-.7-2.2 1.51 1.51 0 0 0-1.6 .1zM149.5 75.2a.66 .66 0 0 1 .7-.1 .66 .66 0 0 1 .4 .6v.5a2.43 2.43 0 0 1-.3 1.7 .64 .64 0 0 1-.7 0 .64 .64 0 0 1-.3-.6 3.3 3.3 0 0 1 .2-2.1z"/>
<path d="M145.3 74.9a1.09 1.09 0 0 0 .4 1.4 1.02 1.02 0 0 0-.5 1.5v.1a1.63 1.63 0 0 0 2.7 0 1.45 1.45 0 0 0-.6-1.6 .93 .93 0 0 0 .5-1 .93 .93 0 0 0-.8-.8 1.39 1.39 0 0 0-1.7 .4zM145.9 76.8a.72 .72 0 0 1 1.1-.1 .72 .72 0 0 1 0 1.1 .72 .72 0 0 1-1.1-.1zM146 75.5a.58 .58 0 0 1 1.1 0 .58 .58 0 0 1-1.1 0z"/>
<path d="M136.8 74.6v2.4a.39 .39 0 0 0-.6 .4 .39 .39 0 0 0 .6 .2v.7a.34 .34 0 0 0 .4 .3 .34 .34 0 0 0 .3-.4v-.6h1.5a.38 .38 0 0 0 .3-.2 .38 .38 0 0 0 0-.4l-1.9-2.6-.3-.1zM137.5 75.4l1.2 1.6h-1.2z"/>
<path d="M133.3 74.7l-.1 .3a.36 .36 0 0 0-.1 .4 .36 .36 0 0 0 .4 .2l.1-.1a.7 .7 0 0 1 .8-.5 .7 .7 0 0 1 .5 .8l.1 .5a1.29 1.29 0 0 0-1.4-.3 1.29 1.29 0 0 0-.8 1.3 1.44 1.44 0 0 0 1.5 1.3 1.44 1.44 0 0 0 1.4-1.4 2.87 2.87 0 0 0-.7-2.6 1.8 1.8 0 0 0-1.7 .1zM133.8 76.6a.75 .75 0 0 1 .9 0 .75 .75 0 0 1 .2 .8 .68 .68 0 0 1-.7 .6 .68 .68 0 0 1-.6-.6z"/>
<path d="M124.2 74.8a1.27 1.27 0 0 0 .5 1.8l.4 .1-.5 .5a1.48 1.48 0 0 0-.6 1.3h.1a.4 .4 0 0 0 .6-.1l.6-.9a.86 .86 0 0 1 .9-.7h.3v1.3a.42 .42 0 0 0 .4 .4 .42 .42 0 0 0 .4-.4v-3.6l-2.3-.1zM124.9 75.3l.2-.2 1.4-.1v1.2l-1.2-.1a.51 .51 0 0 1-.4-.8z"/>
<path d="M120.8 76l-.2 .3a.56 .56 0 0 0 0 .7 .56 .56 0 0 0 .6 .2l1.4 .1a.8 .8 0 0 1-.4 .7 .8 .8 0 0 1-.9-.1l-.1-.1a.31 .31 0 0 0-.5-.2 .31 .31 0 0 0 .1 .5v.1a1.66 1.66 0 0 0 2.4-.3 1.82 1.82 0 0 0-.4-2.2 1.75 1.75 0 0 0-2 .3zM121.3 76.3a.69 .69 0 0 1 .8-.2 .69 .69 0 0 1 .5 .7h-1.3z"/>
</g>
<path d="M126.2 13.8h35.2v7.5h-35.2z" fill-rule="evenodd" fill="#8c8c8c"/>
<g fill="#fff">
<path d="M153.9 15.5h1.1l.5 2.8 .7-2.8h1.1l.7 2.8 .6-2.8h1.1l-1.1 4h-1.1l-.7-2.5-.8 2.5h-1z"/>
<path d="M151.1 15.5h2.2v.8h-.5v2.5h.5v.7h-2.2v-.7h.6v-2.5h-.6z"/>
<path d="M143 15.5h2.9v4h-2.9v-.8h1.9v-1h-1.7v-.7h1.7v-.7h-1.9z"/>
<path d="M141.2 15.5h1v4h-2.9v-.8h1.9z"/>
<path d="M135.9 15.5h2.8v4h-2.8v-.8h1.8v-1h-1.7v-.7h1.7v-.7h-1.8z"/>
<path d="M132 15.8l.3-.2a2.74 2.74 0 0 1 2.3 .2 1.13 1.13 0 0 1 .6 1.1 1.13 1.13 0 0 1-.9 1l-.9 .2a.42 .42 0 0 0-.5 .5 .42 .42 0 0 0 .7 .2h.6l1-.5v.9a3 3 0 0 1-2.8 0 1.12 1.12 0 0 1-.6-1.2 1.12 1.12 0 0 1 1.1-.9l.7-.1a.4 .4 0 0 0 .5-.4 .4 .4 0 0 0-.5-.4l-.9 .1-.7 .3z"/>
<path d="M128.1 15.8l.3-.2a2.74 2.74 0 0 1 2.3 .2 1.13 1.13 0 0 1 .6 1.1 1.13 1.13 0 0 1-.9 1l-.9 .2a.41 .41 0 0 0-.5 .4 .41 .41 0 0 0 .6 .3 2.48 2.48 0 0 0 1.7-.5v.9a3.2 3.2 0 0 1-2.9 0 1.16 1.16 0 0 1-.4-1.3 1.16 1.16 0 0 1 1.2-.8l.5-.1a.4 .4 0 0 0 .5-.4 .4 .4 0 0 0-.5-.4l-.8 .1-.8 .3z"/>
<path d="M148 16.4l.4-.1h.8v1h-.3a.63 .63 0 0 1-.7-.1 .63 .63 0 0 1-.2-.8zM147 16.1a1.37 1.37 0 0 0 .7 1.7l-1.3 1.7h1.2l1.1-1.4h.5v1.4h1v-4h-1.7a1.53 1.53 0 0 0-1.4 .6z"/>
</g>
<g fill="#8c8c8c">
<path d="M140 83.8a.33 .33 0 0 1 .4-.1 .33 .33 0 0 1 .2 .4l.8 2.2 .7-2.2a.32 .32 0 0 1 .4-.3 .32 .32 0 0 1 .2 .5l-.8 2.1a.51 .51 0 0 1-.5 .6 .51 .51 0 0 1-.5-.6l-.9-2.1z"/>
<path d="M137.1 84h.1a1.58 1.58 0 0 1 1.9 .1 1.58 1.58 0 0 1 .4 1.9 1.39 1.39 0 0 1-1.4 1 1.06 1.06 0 0 1-1.2-1.3 .46 .46 0 0 1 .6 .5 .88 .88 0 0 0 .9 .2 .88 .88 0 0 0 .6-.8v-.3a1 1 0 0 0-1-1l-.4 .1-.2 .3a.33 .33 0 0 1-.5 .2 .33 .33 0 0 1 0-.5z"/>
<path d="M133.6 84.4a1.62 1.62 0 0 1 2.3-.3l.1 .1a1.76 1.76 0 0 1-.4 2.6 1.34 1.34 0 0 1-2.1-.9h.1a.27 .27 0 0 1 .3-.2 .27 .27 0 0 1 .2 .3 .85 .85 0 0 0 1 .5 .85 .85 0 0 0 .6-1 1.23 1.23 0 0 0-.5-1.2 1.05 1.05 0 0 0-1.3 .6 .38 .38 0 0 1-.3-.1 .38 .38 0 0 1 0-.4z"/>
</g>
<path d="M131.1 87.4h2.2" fill="none" stroke="#8c8c8c" stroke-width=".17"/>
<g fill="#8c8c8c">
<path d="M127.8 83.8h.9l.5 2.2 .5-1.9a.32 .32 0 0 1 .4-.3h.6v2.8a.3 .3 0 0 1-.3 .4 .3 .3 0 0 1-.3-.4v-2.2l-.5 2.1a.38 .38 0 0 1-.4 .5 .38 .38 0 0 1-.3-.5l-.6-2.1v2.3a.3 .3 0 0 1-.4 .3 .3 .3 0 0 1-.2-.4z"/>
<path d="M124.5 84.3a1.64 1.64 0 0 1 2.4 .1 1.9 1.9 0 0 1-.4 2.4 1.4 1.4 0 0 1-2.1-.7 .31 .31 0 0 1 .2-.4 .31 .31 0 0 1 .4 .3 .83 .83 0 0 0 1.1 .4 .83 .83 0 0 0 .4-1 .87 .87 0 0 0-.6-1.1 .87 .87 0 0 0-1.1 .6 .34 .34 0 0 1-.4-.1 .34 .34 0 0 1 .1-.4z"/>
<path d="M121.2 83.8a.33 .33 0 0 1 .4-.1 .33 .33 0 0 1 .2 .4v1.6a.73 .73 0 0 0 .4 .8 .73 .73 0 0 0 .8-.2l.1-2.2a.34 .34 0 0 1 .4-.3 .34 .34 0 0 1 .3 .3v1.5a1.23 1.23 0 0 1-.6 1.2l-.4 .2a1.3 1.3 0 0 1-1.6-.6z"/>
</g>
<g fill="none" stroke="#8c8c8c" stroke-width=".68">
<circle cx="177.7" cy="14.8" r="13.3"/>
<circle cx="223.3" cy="49.9" r="13.3"/>
<circle cx="177.7" cy="85.1" r="13.3"/>
</g>
<path d="M21.8 .1h216.1v99.7h-216.1v-44h-21.6v-11.7h21.6z" fill="none" stroke="#000" stroke-width=".17"/>
<path d="M21.8 .1h216.1v99.7h-216.1v-44h-21.6v-11.7h21.6z" fill="none" stroke="#5a5a5a" stroke-width=".34"/>
</svg>
